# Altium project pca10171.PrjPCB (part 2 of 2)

## Sheet pca10171_memory.SchDoc: =BoardTitle + ' - Memory'
size A3; Organization: Nordic Semiconductor; DocumentNumber: 6; Revision: 1.0.1; SheetNumber: 6; SheetTotal: 10; Author: KOD1; CompanyName: Nordic Semiconductor; DrawnBy: KOD1; DocumentSize: A3

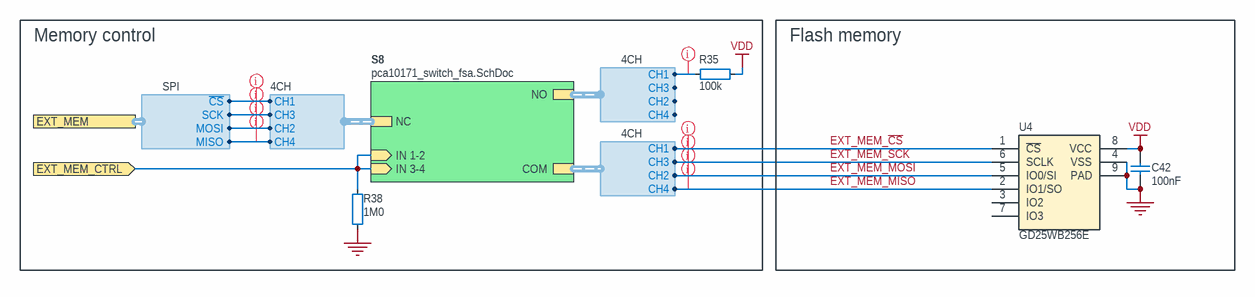
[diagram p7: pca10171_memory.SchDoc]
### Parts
C42  100nF  [CAPC0603X03L_C]
R35  100k  [RESC0603X03L_C]
R38  1M0  [RESC0603X03L_C]
U4  GD25WB256E  [SON127P800X80_HS-9N]

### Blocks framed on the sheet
Memory control: R35 R38
Flash memory: C42 U4

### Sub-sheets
S8 = pca10171_switch_fsa.SchDoc: IN 1-2 (in), COM (harness 4CH), NC (harness 4CH), NO (harness 4CH), IN 3-4 (in)

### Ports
EXT_MEM (harness SPI), EXT_MEM_CTRL (in)

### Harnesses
4CH: CH1, CH2, CH3, CH4
SPI: SCK, ~{CS}, MOSI, MISO

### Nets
GND: C42.1 R38.1 U4.4(VSS) U4.9(PAD)
VDD: C42.2 R35.2 U4.8(VCC)
EXT_MEM_~{CS}: U4.1(~{CS}) ; sheet S8/COM.CH1
EXT_MEM_CTRL: R38.2 ; port EXT_MEM_CTRL, sheet S8/IN 1-2, sheet S8/IN 3-4
EXT_MEM_MISO: U4.2(IO1/SO) ; sheet S8/COM.CH4
EXT_MEM_MOSI: U4.5(IO0/SI) ; sheet S8/COM.CH2
EXT_MEM_SCK: U4.6(SCLK) ; sheet S8/COM.CH3
P0.11: port EXT_MEM.MOSI, sheet S8/NC.CH2
P0.12: port EXT_MEM.MISO, sheet S8/NC.CH4
P0.13/AIN0: port EXT_MEM.SCK, sheet S8/NC.CH3
P0.20/AIN7: port EXT_MEM.~{CS}, sheet S8/NC.CH1
NetR35_1: R35.1 ; sheet S8/NO.CH1

Not connected (* = marked no-connect by the designer): U4 3(IO2) 7(IO3)

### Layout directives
net class GPIO: EXT_MEM_MISO, EXT_MEM_MOSI, EXT_MEM_SCK, EXT_MEM_~{CS}, NetR35_1, P0.11, P0.12, P0.13/AIN0, P0.20/AIN7

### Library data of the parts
C42 = C0201-100n: Capacitor, X5R, ±10%; Manufacturer: N.A.; Part number IPS: 00000001248, 00000002505; Part number Norautron: 262071862; Part number NEMS: 100200078; Note: 16V; Pad Count: 2; Component Status: Active
R35 = R0201-100k: Resistor, ±1%, 0.05W; Manufacturer: N.A.; Part number IPS: 00000001419; Part number Norautron: 26108487; Part number NEMS: 100100080; Pad Count: 2; Note: Chip Res 1%; Component Status: Active
R38 = R0201-1M0: Resistor, ±1%, 0.05W; Manufacturer: N.A.; Part number IPS: 00000001418; Part number Norautron: 26107108; Part number NEMS: 100100093; Note: Chip Res 1%; Pad Count: 2; Component Status: Active
U4 = GD25WB256EYIG: Quad Serial Flash, 256Mbit, 104MHz, 1.65V - 3.6V; Manufacturer: GigaDevice; Part number NEMS: 101900774; Note: N.A.; Pad Count: 8; Component Status: Active

## Sheet pca10171_connectors.SchDoc: =BoardTitle + ' - Connectors'
size A3; Organization: Nordic Semiconductor; DocumentNumber: 7; Revision: 1.0.1; SheetNumber: 7; SheetTotal: 10; Author: KOD1; CompanyName: Nordic Semiconductor; DrawnBy: KOD1; DocumentSize: A3

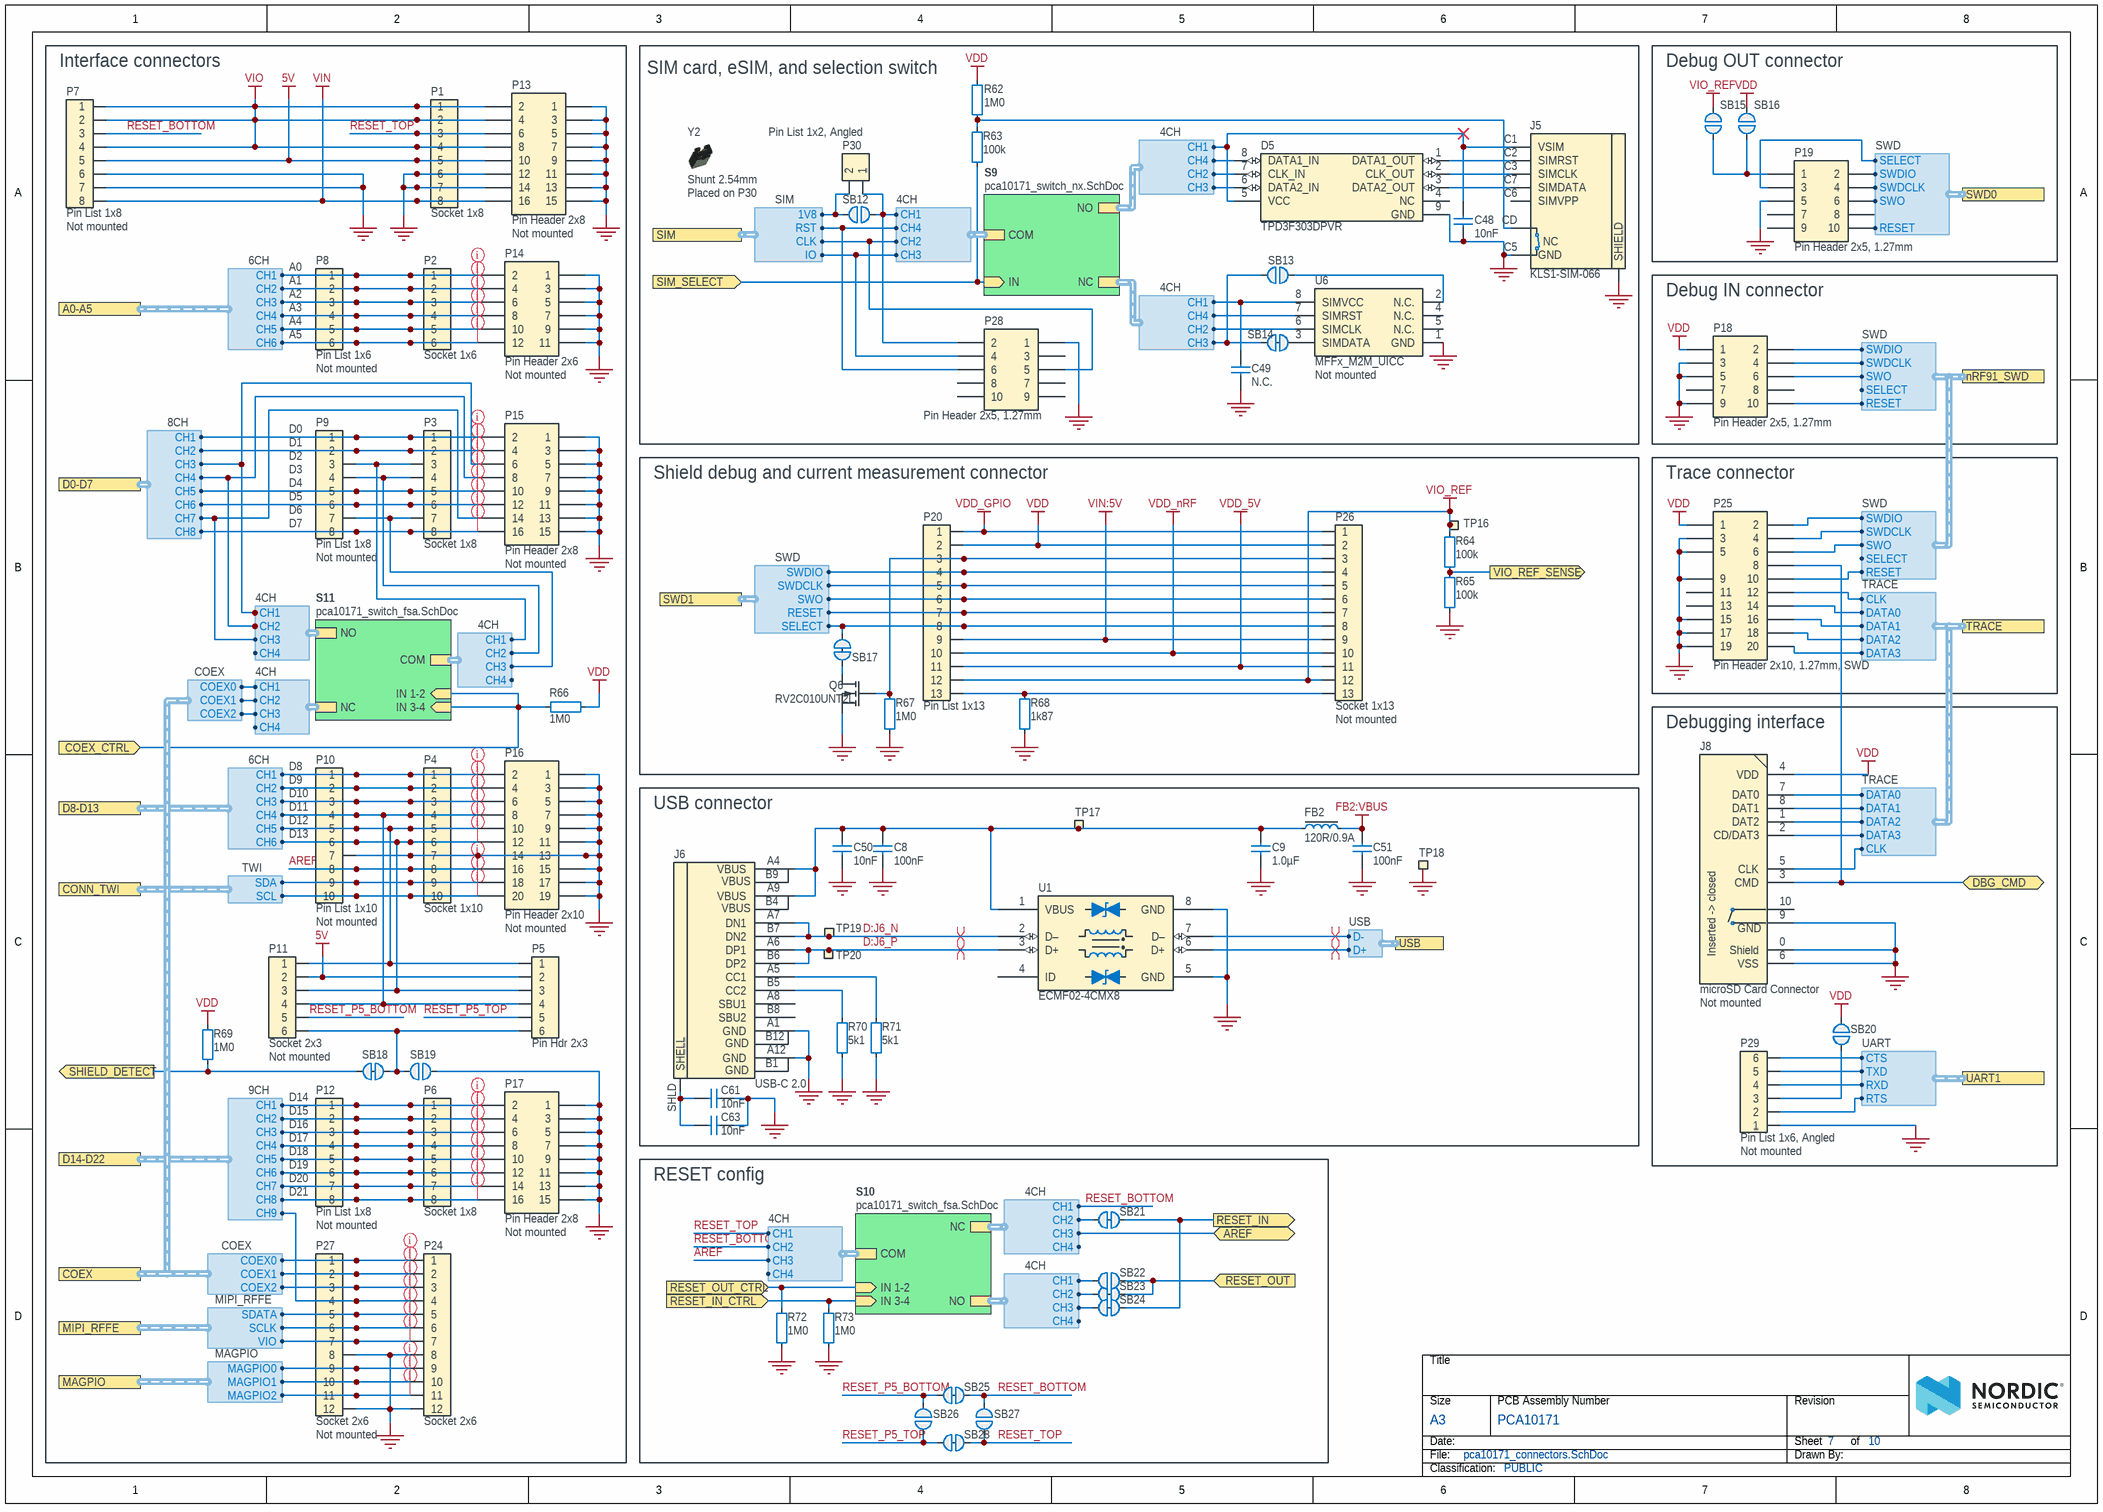
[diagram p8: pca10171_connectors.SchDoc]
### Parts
C8  100nF  [CAPC0603X03L_C]
C9  1.0µF  [CAPC1005X04L]
C48  10nF  [CAPC0603X03L_C]
C49  N.C.  [CAPC0603X03L_C_NC]
C50  10nF  [CAPC0603X03L_C]
C51  100nF  [CAPC0603X03L_C]
C61  10nF  [CAPC1005X04L]
C63  10nF  [CAPC1005X04L]
D5  TPD3F303DPVR  [SON50P210X160X65_HS-9N]
FB2  120R/0.9A  [INDC0603X03L_C]
J5  KLS1-SIM-066  [KLS1-SIM-066]
J6  USB-C 2.0  [SD-80259-001]
J8  microSD Card Connector  Assembly: Not mounted  [Molex_502774-0891]
P1  Socket 1x8  [SOCKET_1x8_SMD]
P2  Socket 1x6  [SOCKET_1x6_SMD]
P3  Socket 1x8  [SOCKET_1x8_SMD]
P4  Socket 1x10  [SOCKET_1x10_SMD]
P5  Pin Hdr 2x3  [HDR_2x3-SMD]
P6  Socket 1x8  [SOCKET_1x8_SMD]
P7  Pin List 1x8  Assembly: Not mounted  [LIST_1x8_SMD-NC]
P8  Pin List 1x6  Assembly: Not mounted  [LIST_1x6_SMD-NC]
P9  Pin List 1x8  Assembly: Not mounted  [LIST_1x8_SMD-NC]
P10  Pin List 1x10  Assembly: Not mounted  [LIST_1x10_SMD-NC]
P11  Socket 2x3  Assembly: Not mounted  [SOCKET_2x3_SMD-2.54mm-bottom-NC]
P12  Pin List 1x8  Assembly: Not mounted  [LIST_1x8_SMD-NC]
P13  Pin Header 2x8  Assembly: Not mounted  [HDR_2x8-NC]
P14  Pin Header 2x6  Assembly: Not mounted  [HDR_2x6-NC]
P15  Pin Header 2x8  Assembly: Not mounted  [HDR_2x8-NC]
P16  Pin Header 2x10  Assembly: Not mounted  [HDR_2x10-NC]
P17  Pin Header 2x8  Assembly: Not mounted  [HDR_2x8-NC]
P18  Pin Header 2x5, 1.27mm  [HDR_2x5-SMD-1.27mm-K]
P19  Pin Header 2x5, 1.27mm  [HDR_2x5-SMD-1.27mm-K]
P20  Pin List 1x13  [LIST_1x13_SMD]
P24  Socket 2x6  [SOCKET_2x6_SMD-2.54mm]
P25  Pin Header 2x10, 1.27mm, SWD  [HDR_2x10-SMD-1.27mm-K-SWD]
P26  Socket 1x13  Assembly: Not mounted  [LIST_1x13_SMD-NC]
P27  Socket 2x6  Assembly: Not mounted  [SOCKET_2x6_SMD-2.54mm]
P28  Pin Header 2x5, 1.27mm  [HDR_2x5-SMD-1.27mm]
P29  Pin List 1x6, Angled  Assembly: Not mounted  [LIST_ANG_1x6-SMD-2.54MM]
P30  Pin List 1x2, Angled  [LIST_ANG_1x2-SMD-2.54MM]
Q6  RV2C010UNT2L  [DFN65P100X40-3L]
R62  1M0  [RESC0603X03L_C]
R63  100k  [RESC0603X03L_C]
R64  100k  [RESC0603X03L_C]
R65  100k  [RESC0603X03L_C]
R66  1M0  [RESC0603X03L_C]
R67  1M0  [RESC0603X03L_C]
R68  1k87  [RESC0603X03L_C]
R69  1M0  [RESC0603X03L_C]
R70  5k1  [RESC0603X03L_C]
R71  5k1  [RESC0603X03L_C]
R72  1M0  [RESC0603X03L_C]
R73  1M0  [RESC0603X03L_C]
SB12  Solderbridge  [Solderbridge]  (value not drawn)  (no BOM)
SB13  Solderbridge  [Solderbridge]  (value not drawn)  (no BOM)
SB14  Solderbridge  [Solderbridge_Shorted]  (value not drawn)  (net tie, no BOM)
SB15  Solderbridge  [Solderbridge]  (value not drawn)  (no BOM)
SB16  Solderbridge  [Solderbridge]  (value not drawn)  (no BOM)
SB17  Solderbridge  [Solderbridge_Shorted]  (value not drawn)  (net tie, no BOM)
SB18  Solderbridge  [Solderbridge_Shorted]  (value not drawn)  (net tie, no BOM)
SB19  Solderbridge  [Solderbridge]  (value not drawn)  (no BOM)
SB20  Solderbridge  [Solderbridge]  (value not drawn)  (no BOM)
SB21  Solderbridge  [Solderbridge_Shorted]  (value not drawn)  (net tie, no BOM)
SB22  Solderbridge  [Solderbridge]  (value not drawn)  (no BOM)
SB23  Solderbridge  [Solderbridge_Shorted]  (value not drawn)  (net tie, no BOM)
SB24  Solderbridge  [Solderbridge_Shorted]  (value not drawn)  (net tie, no BOM)
SB25  Solderbridge  [Solderbridge_Shorted]  (value not drawn)  (net tie, no BOM)
SB26  Solderbridge  [Solderbridge]  (value not drawn)  (no BOM)
SB27  Solderbridge  [Solderbridge]  (value not drawn)  (no BOM)
SB28  Solderbridge  [Solderbridge_Shorted]  (value not drawn)  (net tie, no BOM)
TP16  Ø1.5mm,SMD  [TP_SMD_D1.5mm]  (value not drawn)  (no BOM)
TP17  Ø1.5mm,SMD  [TP_SMD_D1.5mm]  (value not drawn)  (no BOM)
TP18  Ø1.5mm,SMD  [TP_SMD_D1.5mm]  (value not drawn)  (no BOM)
TP19  Ø1.5mm,SMD  [TP_SMD_D1.5mm]  (value not drawn)  (no BOM)
TP20  Ø1.5mm,SMD  [TP_SMD_D1.5mm]  (value not drawn)  (no BOM)
U1  ECMF02-4CMX8  [UFDFN50P120X250X55-8N]
U6  MFFx_M2M_UICC  Assembly: Not mounted  [SON127P600X90_HS-8N]
Y2  Shunt 2.54mm  Assembly: Placed on P30  [Shunt_2.54mm_Horizontal]

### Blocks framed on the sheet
Interface connectors: P1-P17 P24 P27 R66 R69 SB18 SB19
SIM card, eSIM, and selection switch: C48 C49 D5 J5 P28 P30 R62 R63 SB12-SB14 U6 Y2
Debug OUT connector: P19 SB15 SB16
Debug IN connector: P18
Shield debug and current measurement connector: P20 P26 Q6 R64 R65 R67 R68 SB17 TP16
Trace connector: P25
Debugging interface: J8 P29 SB20
USB connector: C8 C9 C50 C51 C61 C63 FB2 J6 R70 R71 TP17-TP20 U1
RESET config: R72 R73 SB21-SB28

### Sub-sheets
S9 = pca10171_switch_nx.SchDoc: IN (in), COM (harness 4CH), NC (harness 4CH), NO (harness 4CH)
S10 = pca10171_switch_fsa.SchDoc: IN 1-2 (in), COM (harness 4CH), NC (harness 4CH), NO (harness 4CH), IN 3-4 (in)
S11 = pca10171_switch_fsa.SchDoc: IN 1-2 (in), COM (harness 4CH), NC (harness 4CH), NO (harness 4CH), IN 3-4 (in)

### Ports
A0-A5 (harness 6CH), AREF (bidir), COEX (harness COEX), COEX_CTRL (in), CONN_TWI (harness TWI), D0-D7 (harness 8CH), D8-D13 (harness 6CH), D14-D22 (harness 9CH), DBG_CMD (bidir), MAGPIO (harness MAGPIO), MIPI_RFFE (harness MIPI_RFFE), nRF91_SWD (harness SWD), RESET_IN (out), RESET_IN_CTRL (in), RESET_OUT (in), RESET_OUT_CTRL (in), SHIELD_DETECT (out), SIM (harness SIM), SIM_SELECT (in), SWD0 (harness SWD), SWD1 (harness SWD), TRACE (harness TRACE), UART1 (harness UART), USB (harness USB), VIO_REF_SENSE (out)

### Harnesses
SWD: SWDIO, SWDCLK, SWO, RESET, SELECT
6CH: CH1, CH2, CH3, CH4, CH5, CH6
8CH: CH1, CH2, CH3, CH4, CH5, CH6, CH7, CH8
COEX: COEX0, COEX2, COEX1
TRACE: CLK, DATA0, DATA1, DATA3, DATA2
USB: D+, D-
UART: RTS, CTS, RXD, TXD
MIPI_RFFE: SDATA, VIO, SCLK
MAGPIO: MAGPIO0, MAGPIO2, MAGPIO1
TWI: SCL, SDA
9CH: CH1, CH2, CH3, CH4, CH5, CH6, CH7, CH8, CH9
4CH: CH1, CH2, CH3, CH4
SIM: CLK, IO, 1V8, RST

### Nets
5V: P1.5 P5.2 P7.5 P11.2 P13.10
FB2:VBUS: C51.2 FB2.2
GND: C8.1 C9.1 C48.2 C49.1 C50.1 C51.1 C61.2 C63.2 D5.9(GND) J5.0(SHIELD) J5.C5(GND) J6.A1(GND) J6.A12(GND) J8.0(Shield) J8.6(VSS) J8.9 P1.6 P1.7 P4.7 P7.6 P7.7 P10.7 P13.1 P13.3 P13.5 P13.7 P13.9 P13.11 P13.12 P13.13 P13.14 P13.15 P14.1 P14.3 P14.5 P14.7 P14.9 P14.11 P15.1 P15.3 P15.5 P15.7 P15.9 P15.11 P15.13 P15.15 P16.1 P16.3 P16.5 P16.7 P16.9 P16.11 P16.13 P16.14 P16.15 P16.17 P16.19 P17.1 P17.3 P17.5 P17.7 P17.9 P17.11 P17.13 P17.15 P18.3 P18.5 P18.9 P19.5 P24.8 P24.12 P25.3 P25.5 P25.9 P25.15 P25.17 P25.19 P27.8 P27.12 P28.1 P29.1 Q6.2(S) R65.1 R67.2 R68.1 R70.1 R71.1 R72.2 R73.1 SB19.1 TP18.1 U1.5(GND) U1.8(GND) U6.1(GND)
VDD: J8.4(VDD) P18.1 P20.2 P25.1 P26.2 R62.1 R66.1 R69.2 SB16.2 SB20.1
VDD_5V: P20.11 P26.11
VDD_GPIO: P20.1 P26.1
VDD_nRF: P20.10 P26.10
VIN: P1.8 P7.8 P13.16
VIN:5V: P20.9 P26.9
VIO: P1.1 P1.2 P1.4 P7.1 P7.2 P7.4 P13.2 P13.4 P13.8
VIO_REF: P20.12 P26.12 R64.1 SB15.2 TP16.1
AREF: P4.8 P10.8 P16.16 ; sheet S10/COM.CH3
COEX0: P24.1 P27.1 ; port COEX.COEX0, sheet S11/NC.CH1
COEX1: P24.2 P27.2 ; port COEX.COEX1, sheet S11/NC.CH2
COEX2: P24.3 P27.3 ; port COEX.COEX2, sheet S11/NC.CH3
COEX_SELECT: R66.2 ; port COEX_CTRL, sheet S11/IN 1-2, sheet S11/IN 3-4
D:J6_N: J6.A7(DN1) J6.B7(DN2) TP19.1 U1.2(D–)
D:J6_P: J6.A6(DP1) J6.B6(DP2) TP20.1 U1.3(D+)
D_N: U1.7(D–) ; port USB.D-
D_P: U1.6(D+) ; port USB.D+
DBG_CMD: J8.3(CMD) P25.8 ; port DBG_CMD
MAGPIO0: P24.9 P27.9 ; port MAGPIO.MAGPIO0
MAGPIO1: P24.10 P27.10 ; port MAGPIO.MAGPIO1
MAGPIO2: P24.11 P27.11 ; port MAGPIO.MAGPIO2
MIPI_SCLK: P24.6 P27.6 ; port MIPI_RFFE.SCLK
MIPI_SDATA: P24.5 P27.5 ; port MIPI_RFFE.SDATA
MIPI_VIO: P24.7 P27.7 ; port MIPI_RFFE.VIO
P0.00: P3.1 P9.1 P15.2 ; port D0-D7.CH1
P0.01: P3.2 P9.2 P15.4 ; port D0-D7.CH2
P0.02: P15.6 ; port D0-D7.CH3, sheet S11/NO.CH1
P0.03: P15.8 ; port D0-D7.CH4, sheet S11/NO.CH2
P0.04: P3.5 P9.5 P15.10 ; port D0-D7.CH5
P0.05: P3.6 P9.6 P15.12 ; port D0-D7.CH6
P0.06: P15.14 ; port D0-D7.CH7, sheet S11/NO.CH3
P0.07: P3.8 P9.8 P15.16 ; port D0-D7.CH8
P0.08: P4.1 P10.1 P16.2 ; port D8-D13.CH1
P0.09: P4.2 P10.2 P16.4 ; port D8-D13.CH2
P0.10: P4.3 P10.3 P16.6 ; port D8-D13.CH3
P0.11: P4.4 P5.4 P10.4 P11.4 P16.8 ; port D8-D13.CH4
P0.12: P4.5 P5.1 P10.5 P11.1 P16.10 ; port D8-D13.CH5
P0.13/AIN0: P4.6 P5.3 P10.6 P11.3 P16.12 ; port D8-D13.CH6
P0.14/AIN1: P2.1 P8.1 P14.2 ; port A0-A5.CH1
P0.15/AIN2: P2.2 P8.2 P14.4 ; port A0-A5.CH2
P0.16/AIN3: P2.3 P8.3 P14.6 ; port A0-A5.CH3
P0.17/AIN4: P2.4 P8.4 P14.8 ; port A0-A5.CH4
P0.18/AIN5: P2.5 P8.5 P14.10 ; port A0-A5.CH5
P0.19/AIN6: P2.6 P8.6 P14.12 ; port A0-A5.CH6
P0.20/AIN7: port AREF, sheet S10/NC.CH3
P0.21: J8.5(CLK) P6.1 P12.1 P17.2 P25.12 SB22.1 SB23.1 ; port RESET_OUT, port TRACE.CLK, port D14-D22.CH1
P0.22: J8.7(DAT0) P6.2 P12.2 P17.4 P18.6 P25.6 P25.14 ; port nRF91_SWD.SWO, port TRACE.DATA0, port D14-D22.CH2
P0.23: J8.8(DAT1) P6.3 P12.3 P17.6 P25.16 ; port TRACE.DATA1, port D14-D22.CH3
P0.24: J8.1(DAT2) P6.4 P12.4 P17.8 P25.18 ; port TRACE.DATA2, port D14-D22.CH4
P0.25: J8.2(CD/DAT3) P6.5 P12.5 P17.10 P25.20 ; port TRACE.DATA3, port D14-D22.CH5
P0.26: P6.6 P12.6 P17.12 ; port D14-D22.CH6
P0.27: P6.7 P12.7 P17.14 ; port D14-D22.CH7
P0.28: P6.8 P12.8 P17.16 ; port D14-D22.CH8
P0.29: P24.4 P27.4 ; port D14-D22.CH9
P0.30: P4.9 P10.9 P16.18 ; port CONN_TWI.SDA
P0.31: P4.10 P10.10 P16.20 ; port CONN_TWI.SCL
RESET: P18.10 P25.10 ; port nRF91_SWD.RESET
RESET_BOTTOM: P7.3 SB25.1 SB27.1 ; sheet S10/NC.CH1, sheet S10/COM.CH2
RESET_BUTTON: SB21.2 SB24.2 ; port RESET_IN
RESET_IN_CTRL: R73.2 ; port RESET_IN_CTRL, sheet S10/IN 3-4
RESET_OUT_CTRL: R72.1 ; port RESET_OUT_CTRL, sheet S10/IN 1-2
RESET_P5_BOTTOM: P11.5 SB25.2 SB26.2
RESET_P5_TOP: P5.5 SB26.1 SB28.2
RESET_TOP: P1.3 P13.6 SB27.2 SB28.1 ; sheet S10/COM.CH1
SHIELD_DETECT: R69.1 SB18.2 ; port SHIELD_DETECT
SIM_1V8: P30.2 SB12.1 ; port SIM.1V8
SIM_CLK: P28.5 ; sheet S9/COM.CH2, port SIM.CLK
SIM_IO: P28.4 ; sheet S9/COM.CH3, port SIM.IO
SIM_RST: P28.6 ; sheet S9/COM.CH4, port SIM.RST
SIM_SELECT: R63.1 ; port SIM_SELECT, sheet S9/IN
SWD0_SEL: P19.3 ; port SWD0.SELECT
SWD0_SWO: P19.6 ; port SWD0.SWO
SWD1_SEL: P20.8 P26.8 SB17.2 ; port SWD1.SELECT
SWD1_SWO: P20.6 P26.6 ; port SWD1.SWO
SWDCLK: P18.4 P25.4 ; port nRF91_SWD.SWDCLK
SWDIO: P18.2 P25.2 ; port nRF91_SWD.SWDIO
VIO_REF_SENSE: R64.2 R65.2 ; port VIO_REF_SENSE
NetC8_2: C8.2 C9.2 C50.2 FB2.1 J6.A4(VBUS) J6.A9(VBUS) TP17.1 U1.1(VBUS)
NetC48_1: C48.1 D5.5(VCC) J5.C1(VSIM) ; sheet S9/NO.CH1
NetC49_2: C49.2 U6.8(SIMVCC) ; sheet S9/NC.CH1
NetC61_1: C61.1 C63.1 J6.SHLD(SHELL)
NetD5_1: D5.1(DATA1_OUT) J5.C2(SIMRST)
NetD5_2: D5.2(CLK_OUT) J5.C3(SIMCLK)
NetD5_3: D5.3(DATA2_OUT) J5.C7(SIMDATA)
NetD5_6: D5.6(DATA2_IN) ; sheet S9/NO.CH3
NetD5_7: D5.7(CLK_IN) ; sheet S9/NO.CH2
NetD5_8: D5.8(DATA1_IN) ; sheet S9/NO.CH4
NetJ5_CD: J5.CD R62.2 R63.2
NetJ6_A5: J6.A5(CC1) R71.2
NetJ6_B5: J6.B5(CC2) R70.2
NetP3_3: P3.3 P9.3 ; sheet S11/COM.CH1
NetP3_4: P3.4 P9.4 ; sheet S11/COM.CH2
NetP3_7: P3.7 P9.7 ; sheet S11/COM.CH3
NetP5_6: P5.6 P11.6 SB18.1 SB19.2
NetP19_1: P19.1 SB15.1 SB16.1
NetP19_2: P19.2 ; port SWD0.SWDIO
NetP19_4: P19.4 ; port SWD0.SWDCLK
NetP19_10: P19.10 ; port SWD0.RESET
NetP20_3: P20.3 P26.3 Q6.1(G) R67.1
NetP20_4: P20.4 P26.4 ; port SWD1.SWDIO
NetP20_5: P20.5 P26.5 ; port SWD1.SWDCLK
NetP20_7: P20.7 P26.7 ; port SWD1.RESET
NetP20_13: P20.13 P26.13 R68.2
NetP28_2: P28.2 P30.1 SB12.2 ; sheet S9/COM.CH1
NetP29_2: P29.2 ; port UART1.RTS
NetP29_3: P29.3 SB20.2
NetP29_4: P29.4 ; port UART1.RXD
NetP29_5: P29.5 ; port UART1.TXD
NetP29_6: P29.6 ; port UART1.CTS
NetQ6_3: Q6.3(D) SB17.1
NetSB13_1: SB13.1 U6.2(N.C.)
NetSB13_2: SB13.2 SB14.2 ; sheet S9/NC.CH3
NetSB14_1: SB14.1 U6.3(SIMDATA)
NetSB21_1: SB21.1 ; sheet S10/NC.CH2
NetSB22_2: SB22.2 ; sheet S10/NO.CH1
NetSB23_2: SB23.2 ; sheet S10/NO.CH2
NetSB24_1: SB24.1 ; sheet S10/NO.CH3
NetU6_6: U6.6(SIMCLK) ; sheet S9/NC.CH2
NetU6_7: U6.7(SIMRST) ; sheet S9/NC.CH4

Not connected (* = marked no-connect by the designer): D5 4(NC); J5 C6(SIMVPP); J6 A8(SBU1) B8(SBU2); J8 10; P18 7 8; P19 7 8 9; P25 11 13; P28 3 7 8 9 10; U1 4(ID); U6 4(N.C.) 5(N.C.)

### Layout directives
net class GPIO: AREF, COEX0, COEX1, COEX2, MAGPIO0, MAGPIO1, MAGPIO2, MIPI_SCLK, MIPI_SDATA, MIPI_VIO, P0.00, P0.01, P0.02, P0.03, P0.04, P0.05, P0.06, P0.07, P0.08, P0.09, P0.10, P0.11, P0.12, P0.13/AIN0, P0.14/AIN1, P0.15/AIN2, P0.16/AIN3, P0.17/AIN4, P0.18/AIN5, P0.19/AIN6, P0.21, P0.22, P0.23, P0.24, P0.25, P0.26, P0.27, P0.28, P0.29, P0.30, P0.31
differential pair; differential pair class D:J6; net class USB: D:J6_N, D:J6_P
differential pair; differential pair class IMCU; net class USB: D_N, D_P

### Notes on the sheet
- (near P8) A0
- (near P8) A1
- (near P8) A2
- (near P8) A3
- (near P8) A4
- (near P8) A5
- (near P9) D0
- (near P9) D1
- (near P9) D2
- (near P9) D3
- (near P9) D4
- (near P9) D5
- (near P9) D6
- (near P9) D7
- (near P10) D8
- (near P10) D9
- (near P10) D10
- (near P10) D11
- (near P10) D12
- (near P10) D13
- (near P12) D14
- (near P12) D15
- (near P12) D16
- (near P12) D17
- (near P12) D18
- (near P12) D19
- (near P12) D20
- (near P12) D21

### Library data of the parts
C8 C51 = C0201-100n: as C42 on sheet pca10171_memory
C9 = C0402-1µ0-16V-X5R: Capacitor, Ceramic, X5R, ±10%, 16V; Manufacturer: Murata; Manufacturer Part Number: GRT155R61C105KE01D; Part number NEMS: 100200452; Artikkelnr Noca: N.A.; Pad Count: 2; Component Status: Active
C48 C50 = C0201-10n: Capacitor, X7R, ±10%; Manufacturer: N.A.; Part number IPS: 00000003480; Part number Norautron: 26621779; Part number NEMS: 100200067; Note: 10V; Pad Count: 2; Component Status: Active
C49 = C0201-N.C.: Not mounted; Manufacturer: N.A.; Part number NEMS: 100200001; Note: Chip Cap; Assembly: Not mounted; Pad Count: 2; Component Status: Active
C61 C63 = C0402-10n: Capacitor, X7R, ±10%; Manufacturer: N.A.; Part number IPS: 00000007784; Part number NEMS: 100200173; Component Status: Active; Pad Count: 2; Note: 16V; Artikkelnr Noca: 20039166
D5 = TPD3F303DPVR: ESD Protection and EMI Filter for SIM Card Interface; Manufacturer: Texas Instruments; Part number NEMS: 101900729; Note: N.A.; Pad Count: 8; Component Status: Active
FB2 = FB0201-120R@100M-900mA-BLM03PX121SN1D: Ferrite Bead, 120 Ohm @ 100MHz, 900mA, 160 mOhm Max; Manufacturer: Murata; Part number NEMS: 100300405; Component Status: Active; Pad Count: 2; Note: N.A.
J5 = L-KLS1-SIM-066-(6+1)P-H1.37-R: Nano SIM Card Connector, Push-Push, 6-Pin, H1.37mm, with CD Pin; Manufacturer: KLS Electronic; Part number NEMS: 100500776; Note: N.A.; Pad Count: 7; Component Status: Active
J6 = 80259-1021: USB-C Receptacle, 16 Pin, USB 2.0; Manufacturer: Bellweather Electronic Corp.; Part number NEMS: 100500830; Component Status: Active; Pad Count: 16; Note: N.A.; System: Connector
J8 = Molex_502774-0891: 1.10mm Pitch microSD Memory Card Connector, Reverse Mount Surface Mount, Push-Push Type; Manufacturer: Molex; Part number IPS: 00000001284; Part number NEMS: 100500509; Note: N.A.; Pad Count: 14; Component Status: Active
P1 P3 P6 = Socket 1x8 SMD: Socket 1x8, 2.54mm (100mil), SMD; Manufacturer: WCON; Manufacturer Part Number: 2171-108MS0CUNR1; Part number IPS: 00000009963; Part number Norautron: 26032369; Part number NEMS: 100500412; Note: N.A.; Artikkelnr Noca: 55030002; Pad Count: 8; Component Status: Active; System: Connector
P2 = Socket 1x6 SMD: Socket 1x6, 2.54mm (100mil), SMD; Manufacturer: WCON; Manufacturer Part Number: 2171-106MS0CUNR1; Part number IPS: 00000009964; Part number Norautron: 26032370; Part number NEMS: 100500408; Note: N.A.; Artikkelnr Noca: 55030001; Pad Count: 6; Component Status: Active; System: Connector
P4 = Socket 1x10 SMD: Socket 1x10, 2.54mm (100mil), SMD; Manufacturer: WCON; Manufacturer Part Number: 2171-110MS0CUNR1; Part number IPS: 00000009965; Part number Norautron: 26032371; Part number NEMS: 100500416; Note: N.A.; Artikkelnr Noca: 55030004; Pad Count: 10; Component Status: Active; System: Connector
P5 = Pin Header 2x3 SMD: Pin Header 2x3, 2.54mm (100mil) SMD; Manufacturer: WCON; Manufacturer Part Number: 1125-1203S0M116R1; Part number IPS: 00000009966; Part number Norautron: N.A.; Part number NEMS: 100500242; Artikkelnr Noca: 55010007; Pad Count: 6; Component Status: Active; System: Connector
P7 P9 P12 = Pin List 1x8 SMD, N.C.: Pin List 1x8, 2.54mm (100mil), SMD; Manufacturer: WCON; Manufacturer Part Number: 1125-1108S0M116R2; Part number NEMS: 100500330; Note: N.A.; Artikkelnr Noca: 55010006; Pad Count: 8; Component Status: Active; System: Connector
P8 = Pin List 1x6 SMD, N.C.: Pin List 1x6, 2.54mm (100mil), SMD; Manufacturer: WCON; Manufacturer Part Number: 1125-1106S0M116R2; Part number NEMS: 100500321; Note: N.A.; Artikkelnr Noca: 55010026; Pad Count: 6; Component Status: Active; System: Connector
P10 = Pin List 1x10 SMD, N.C.: Pin List 1x10, 2.54mm (100mil), SMD; Manufacturer: WCON; Manufacturer Part Number: 1125-1110S0M116R2; Part number NEMS: 100500338; Note: N.A.; Artikkelnr Noca: 55010028; Pad Count: 10; Component Status: Active; System: Connector
P11 = Socket 2x3 SMD Bottom, N.C.: Socket 2x3, 2.54mm (100mil), SMD; Manufacturer: WCON; Manufacturer Part Number: 2171-203MS0CUNR1; Part number NEMS: 100500434; Note: N.A.; Artikkelnr Noca: 55030010; Pad Count: 6; Component Status: Active; System: Connector
P13 P15 P17 = Pin Header 2x8, N.C.: Pin Header 2x8, 2.54mm (100mil); Manufacturer: N.A.; Part number NEMS: 100500270; Pad Count: 16; Component Status: Active; System: Connector
P14 = Pin Header 2x6, N.C.: Pin Header 2x6, 2.54mm (100mil); Manufacturer: N.A.; Part number NEMS: 100500265; Pad Count: 12; Component Status: Active; System: Connector
P16 = Pin Header 2x10, N.C.: Pin Header 2x10, 2.54mm (100mil); Manufacturer: N.A.; Part number NEMS: 100500274; Pad Count: 20; Component Status: Active; System: Connector
P18 P19 = Pin Header 2x5 SMD, 1.27mm, KS: Pin Header 2x5, 1.27mm (50mil), SMD, Keying Shroud; Manufacturer: WCON; Manufacturer Part Number: 3132-10MS0BK00R1; Part number IPS: 00000009968; Part number NEMS: 100500261; Note: N.A.; Artikkelnr Noca: 55010009; Pad Count: 10; Component Status: Active; System: Connector
P20 = Pin List 1x13 SMD: Pin List 1x13, 2.54mm (100mil), SMD; Manufacturer: N.A.; Part number IPS: 00000002499; Part number NEMS: 100500345; Pad Count: 13; Component Status: Active; System: Connector
P24 P27 = Socket 2x6 SMD: Socket 2x6, 2.54mm (100mil), SMD; Manufacturer: WCON; Manufacturer Part Number: 2171-206MS0CUNR1; Part number NEMS: 100500439; Note: N.A.; Pad Count: 12; Component Status: Active; System: Connector
P25 = Pin Header 2x10 SMD, 1.27mm, KS, SWD (Cabcon): Pin Header 2x10, 1.27mm (50mil), SMD, Keying Shroud, Removed Pin 7; Manufacturer: WCON; Manufacturer Part Number: 3132-20MS0BK00R3; Part number NEMS: 100500841,100500280; Note: N.A.; Pad Count: 19; Component Status: Active; System: Connector
P26 = Socket 1x13 SMD, N.C.: Socket 1x13, 2.54mm (100mil), SMD; Manufacturer: WCON; Manufacturer Part Number: 2171-113MS0CUNR1; Part number NEMS: 100500422; Note: N.A.; Pad Count: 13; Component Status: Active; System: Connector
P28 = Pin Header 2x5 SMD, 1.27mm: Pin Header 2x5, 1.27mm (50mil), SMD; Manufacturer: WCON; Manufacturer Part Number: 1325-1205S0M078R1; Part number IPS: 00000009970; Part number NEMS: 100500259; Note: N.A.; Artikkelnr Noca: 55019196; Pad Count: 10; Component Status: Active; System: Connector
P29 = Pin List Ang 1x6 SMD, 2.54mm: Pin List 1x6, 2.54mm (100mil), Right Angled, SMD; Manufacturer: N.A.; Part number IPS: 00000003922; Part number NEMS: 100500362; Pad Count: 6; Component Status: Active; System: Connector
P30 = Pin List Ang 1x2 SMD, 2.54mm: Pin List 1x2, 2.54mm (100mil), Right Angled, SMD; Manufacturer: WCON; Manufacturer Part Number: 1125B-1102S0Z135R2; Part number IPS: 00000009972; Part number NEMS: 100500354; Note: N.A.; Artikkelnr Noca: 55010023; Pad Count: 2; Component Status: Active; System: Connector
Q6 = RV2C010UNT2L: N-Channel MOSFET, 20V, 1A, 470mOhm, 400mW; Manufacturer: Rohm Semiconductor; Part number IPS: 00000009976; Part number Norautron: 26320026; Part number NEMS: 101300132; Note: N.A.; Artikkelnr Noca: 35010020; Pad Count: 3; Component Status: Active
R62 R66 R67 R69 R72 R73 = R0201-1M0: as R38 on sheet pca10171_memory
R63-R65 = R0201-100k: Resistor, ±1%, 0.05W; Manufacturer: N.A.; Part number IPS: 00000001419; Part number Norautron: 26108487; Part number NEMS: 100100080; Note: Chip Res 1%; Pad Count: 2; Component Status: Active
R68 = R0201-1k87: Resistor, ±1%, 0.05W; Manufacturer: N.A.; Part number NEMS: 100100050; Note: Chip Res 1%; Pad Count: 2; Component Status: Active
R70 R71 = R0201-5k1: Resistor, ±1%, 0.05W; Manufacturer: N.A.; Part number Norautron: 26192285; Part number NEMS: 100100565; Pad Count: 2; Note: Chip Res 1%; Component Status: Active
SB12 SB13 SB15 SB16 SB19 SB20 SB22 SB26 SB27 = Solderbridge: Manufacturer: N.A.; Part number NEMS: 100500458; Pad Count: 2; Component Status: Active; System: Connector
SB14 SB18 SB21 SB23-SB25 SB28 = Solderbridge Shorted: Shorted Solderbridge; Manufacturer: N.A.; Part number NEMS: 100500459; Pad Count: 2; Component Status: Active; System: Connector
SB17 = Solderbridge Shorted: Shorted Solderbridge; Manufacturer: N.A.; Part number NEMS: 100500459; Component Status: Active; Pad Count: 2; System: Connector
TP16-TP20 = TP_SMD_Ø1.5MM: 1.5mm circular SMD testpad; Manufacturer: Nordic Semiconductor; Manufacturer Part Number: N.A.; Part number NEMS: 100500477; Pad Count: 1; Component Status: Active
U1 = ECMF02-4CMX8: 2 Line Common mode filter with ESD protection for USB 2.0 interface; Manufacturer: STMicroelectronics; Part number NEMS: 100800034; Component Status: Active; Pad Count: 8; Note: N.A.
U6 = M2M_UICC: M2M UICC SIM Card; Manufacturer: N.A.; Part number NEMS: 101900595; Pad Count: 8; Component Status: Active
Y2 = SHUNT JUMPER 2.54mm BLACK GOLD Horizontal (obsolete): Shunt Jumper 2.54mm Black; Manufacturer: 3M; Manufacturer Part Number: 969102-0000-DA; Part number IPS: 00000001916; Part number Norautron: N.A.; Part number NEMS: 100500644; Note: SHUNT JUMPER .1" BLACK GOLD, h=6.00mm, w=5.00mm; Artikkelnr Noca: 56099001; Pad Count: 2; System: Connector

## Sheet pca10171_power_supply.SchDoc: =BoardTitle + ' - Power Supply'
size A3; Organization: Nordic Semiconductor; DocumentNumber: 8; Revision: 1.0.1; SheetNumber: 8; SheetTotal: 10; Author: KOD1; CompanyName: Nordic Semiconductor; DrawnBy: KOD1; DocumentSize: A3

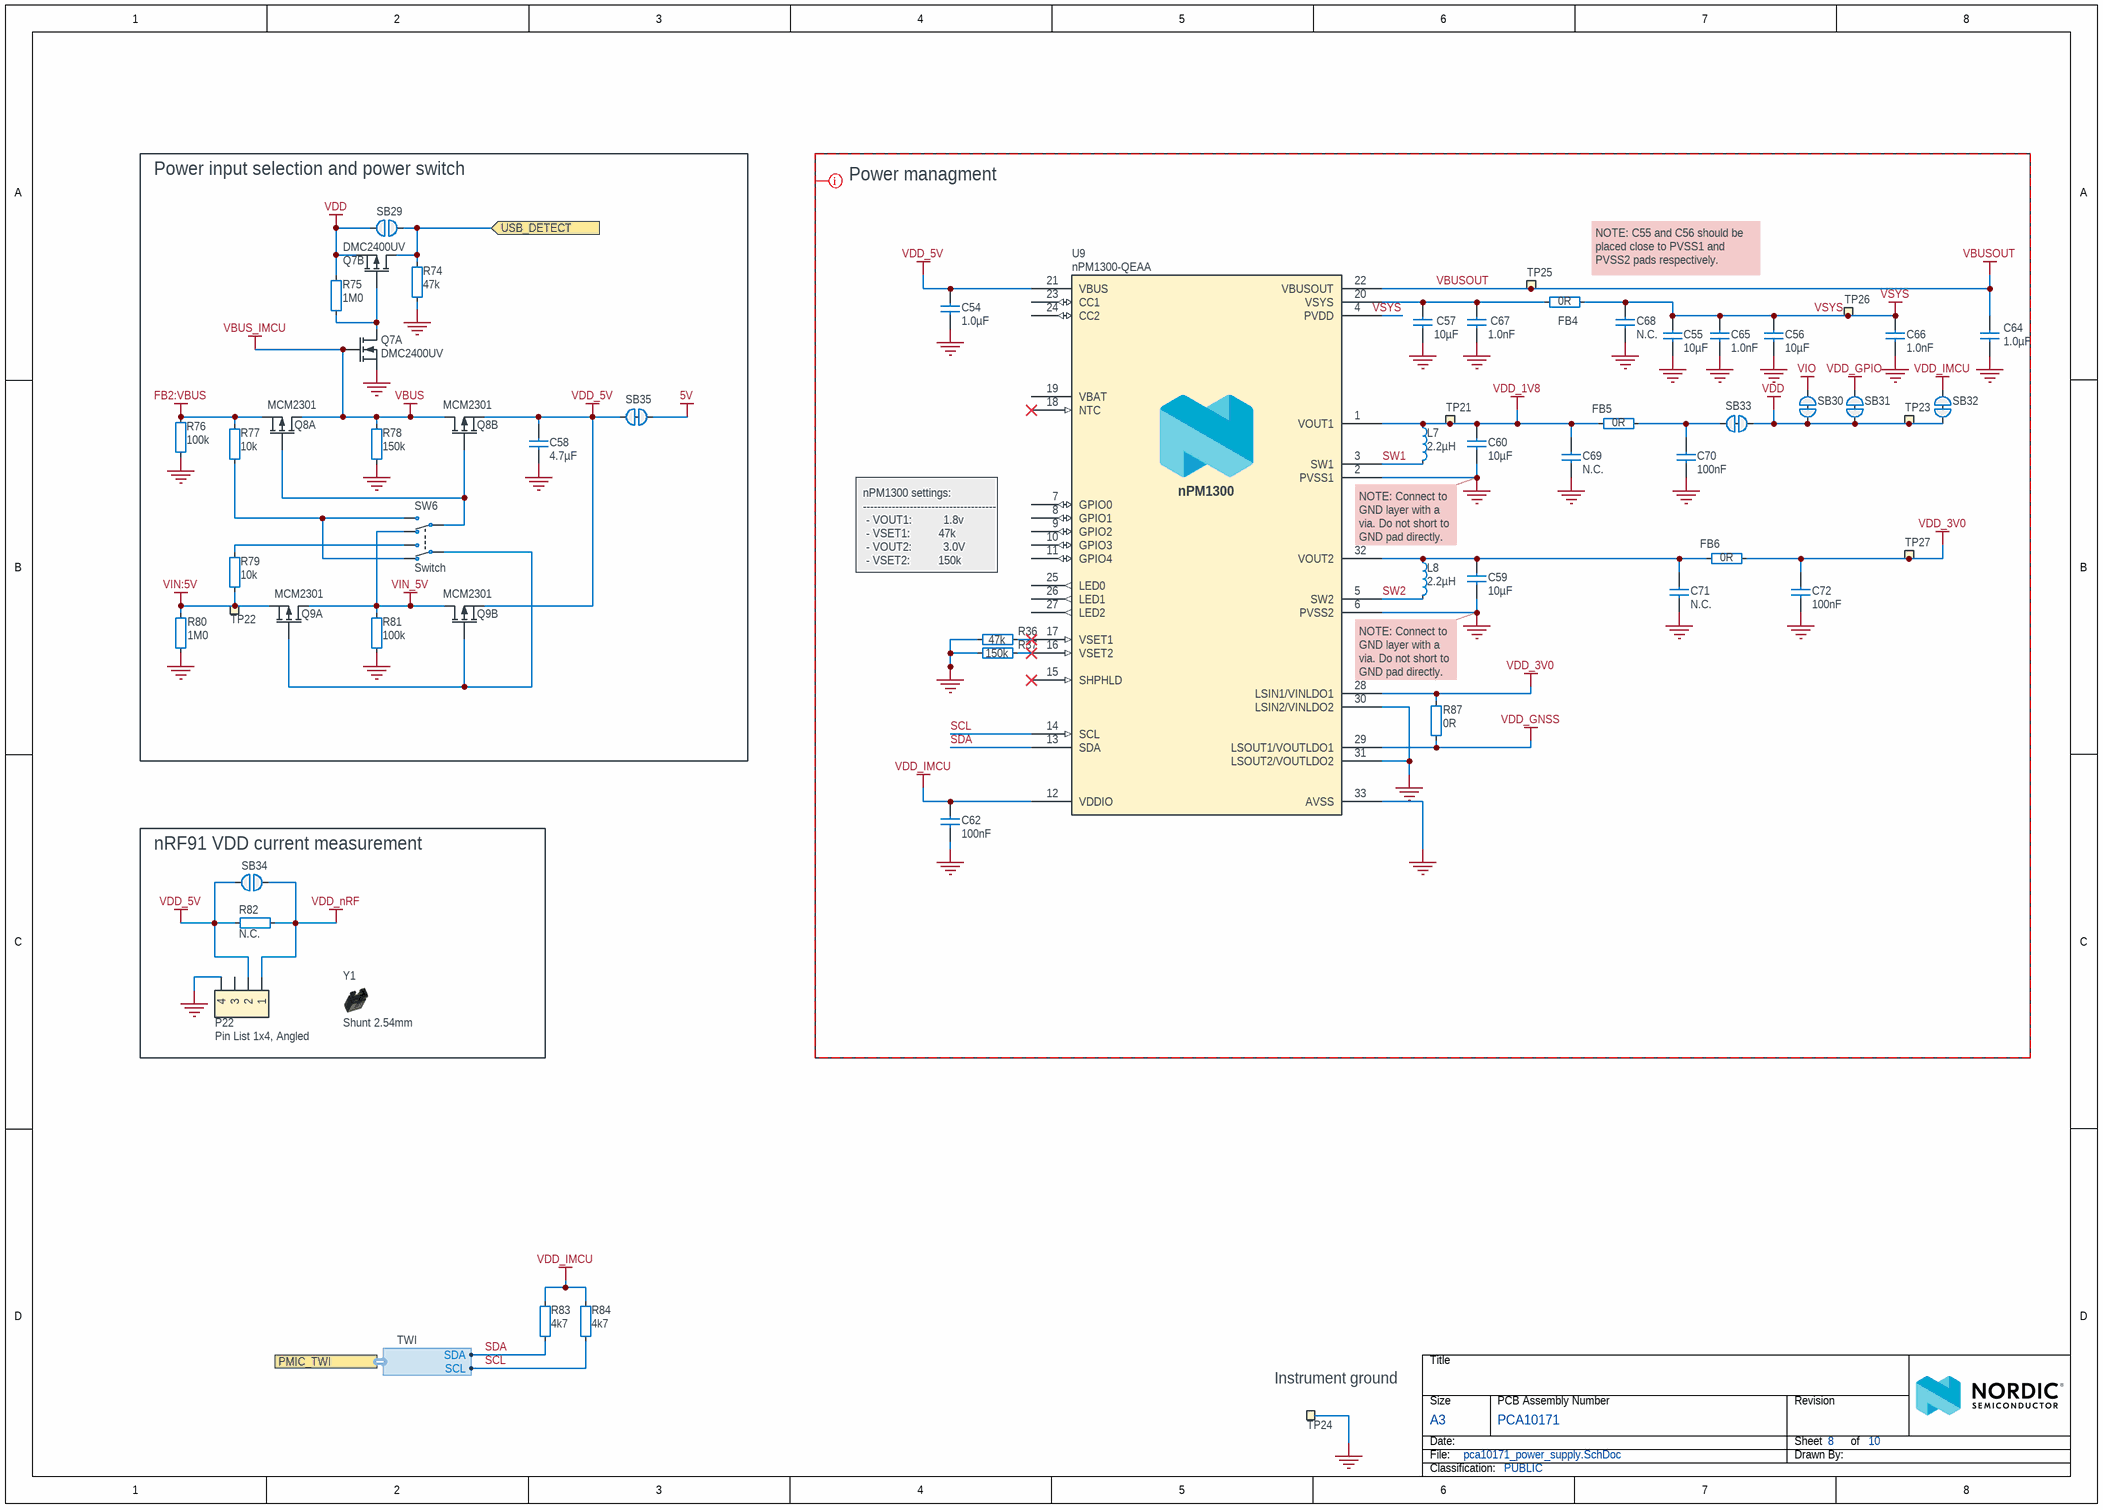
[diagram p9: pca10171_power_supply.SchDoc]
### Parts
C54  1.0µF  [CAPC1608X06L]
C55  10µF  [CAPC1608X06L]
C56  10µF  [CAPC1608X06L]
C57  10µF  [CAPC1608X06L]
C58  4.7µF  [CAPC1608X06L]
C59  10µF  [CAPC1608X06L]
C60  10µF  [CAPC1608X06L]
C62  100nF  [CAPC0603X03L_C]
C64  1.0µF  [CAPC1005X04L]
C65  1.0nF  [CAPC0603X03L_C]
C66  1.0nF  [CAPC0603X03L_C]
C67  1.0nF  [CAPC0603X03L_C]
C68  N.C.  [CAPC1608X06L_NC]
C69  N.C.  [CAPC1608X06L_NC]
C70  100nF  [CAPC1608X06L]
C71  N.C.  [CAPC1608X06L_NC]
C72  100nF  [CAPC1608X06L]
FB4  0R  [RESC2012X11L]
FB5  0R  [RESC2012X11L]
FB6  0R  [RESC2012X11L]
L7  2.2µH  [INDC2016X10N]
L8  2.2µH  [INDC2016X10N]
P22  Pin List 1x4, Angled  [LIST_ANG_1x4-SMD-2.54MM]
Q7  DMC2400UV  [SOTFL50P162X60-6N]  (parts A,B of 2)
Q8  MCM2301  [DFN65P200X200X80_HS-6N]  (parts A,B of 2)
Q9  MCM2301  [DFN65P200X200X80_HS-6N]  (parts A,B of 2)
R36  47k  [RESC0603X03L_C]
R37  150k  [RESC0603X03L_C]
R74  47k  [RESC0603X03L_C]
R75  1M0  [RESC0603X03L_C]
R76  100k  [RESC0603X03L_C]
R77  10k  [RESC0603X03L_C]
R78  150k  [RESC0603X03L_C]
R79  10k  [RESC0603X03L_C]
R80  1M0  [RESC0603X03L_C]
R81  100k  [RESC0603X03L_C]
R82  N.C.  [RESC1005X04L_NC]
R83  4k7  [RESC0603X03L_C]
R84  4k7  [RESC0603X03L_C]
R87  0R  [RESC0603X03L_C]
SB29  Solderbridge  [Solderbridge]  (value not drawn)  (no BOM)
SB30  Solderbridge  [Solderbridge_Shorted_Power]  (value not drawn)  (net tie, no BOM)
SB31  Solderbridge  [Solderbridge_Shorted_Power]  (value not drawn)  (net tie, no BOM)
SB32  Solderbridge  [Solderbridge_Shorted]  (value not drawn)  (net tie, no BOM)
SB33  Solderbridge  [Solderbridge_Shorted_Power]  (value not drawn)  (net tie, no BOM)
SB34  Solderbridge  [Solderbridge]  (value not drawn)  (no BOM)
SB35  Solderbridge  [Solderbridge_Shorted_Power]  (value not drawn)  (net tie, no BOM)
SW6  Switch  [JS102011JAQN]
TP21  Ø1.5mm,SMD  [TP_SMD_D1.5mm]  (value not drawn)  (no BOM)
TP22  Ø1.5mm,SMD  [TP_SMD_D1.5mm]  (value not drawn)  (no BOM)
TP23  Ø1.5mm,SMD  [TP_SMD_D1.5mm]  (value not drawn)  (no BOM)
TP24  TP  [TESTPAD-TH]  (value not drawn)  (no BOM)
TP25  Ø1.5mm,SMD  [TP_SMD_D1.5mm]  (value not drawn)  (no BOM)
TP26  Ø1.5mm,SMD  [TP_SMD_D1.5mm]  (value not drawn)  (no BOM)
TP27  Ø1.5mm,SMD  [TP_SMD_D1.5mm]  (value not drawn)  (no BOM)
U9  nPM1300-QEAA  [Nordic_QFN50P500X500X90-33N]
Y1  Shunt 2.54mm  [Shunt_2.54mm_Horizontal]

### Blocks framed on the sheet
Power input selection and power switch: C58 Q7-Q9 R74-R81 SB29 SB35 SW6 TP22
Power managment: C54-C57 C59 C60 C62 C64-C72 FB4-FB6 L7 L8 R36 R37 R87 SB30-SB33 TP21 TP23 TP25-TP27 U9
nRF91 VDD current measurement: P22 R82 SB34 Y1

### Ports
PMIC_TWI (harness TWI), USB_DETECT (in)

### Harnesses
TWI: SCL, SDA

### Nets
5V: SB35.2
FB2:VBUS: Q8.1(S1) R76.1 R77.1
GND: C54.1 C55.1 C56.1 C57.1 C58.1 C59.1 C60.1 C62.2 C64.1 C65.1 C66.1 C67.1 C68.1 C69.1 C70.1 C71.1 C72.1 P22.4 Q7.1(S1) R36.2 R37.2 R74.1 R76.2 R78.1 R80.2 R81.2 TP24.1 U9.2(PVSS1) U9.6(PVSS2) U9.30(LSIN2/VINLDO2) U9.31(LSOUT2/VOUTLDO2) U9.33(AVSS)
VBUS: Q7.2(G1) Q8.3(D2) Q8.6(D1) R78.2  [also labelled VBUS_IMCU]
VBUSOUT: C64.2 TP25.1 U9.22(VBUSOUT)
VDD: Q7.4(S2) R75.1 SB29.1 SB30.2 SB31.1 SB32.1 SB33.2 TP23.1
VDD_1V8: C60.2 C69.2 FB5.1 L7.1 TP21.1 U9.1(VOUT1)
VDD_3V0: C72.2 FB6.2 R87.1 TP27.1 U9.28(LSIN1/VINLDO1)
VDD_5V: C54.2 C58.2 P22.2 Q8.4(S2) Q9.4(S2) R82.2 SB34.2 SB35.1 U9.21(VBUS)
VDD_GNSS: R87.2 U9.29(LSOUT1/VOUTLDO1)
VDD_GPIO: SB31.2
VDD_IMCU: C62.1 R83.2 R84.2 SB32.2 U9.12(VDDIO)
VDD_nRF: P22.1 R82.1 SB34.1
VIN:5V: Q9.1(S1) R79.2 R80.1 TP22.1
VIN_5V: Q9.3(D2) Q9.6(D1) R81.1 SW6.6(N.C-2)
VIO: SB30.1
VSYS: C55.2 C56.2 C65.2 C66.2 C68.2 FB4.2 TP26.1 U9.4(PVDD)
SCL: R84.1 U9.14(SCL) ; port PMIC_TWI.SCL  [project net IMCU_SCL]
SDA: R83.1 U9.13(SDA) ; port PMIC_TWI.SDA  [project net IMCU_SDA]
SW1: L7.2 U9.3(SW1)
SW2: L8.2 U9.5(SW2)
USB_DETECT: Q7.3(D2) R74.2 SB29.2 ; port USB_DETECT
NetC57_2: C57.2 C67.2 FB4.1 U9.20(VSYS)
NetC59_2: C59.2 C71.2 FB6.1 L8.1 U9.32(VOUT2)
NetC70_2: C70.2 FB5.2 SB33.1
NetQ7_5: Q7.5(G2) Q7.6(D1) R75.2
NetQ8_2: Q8.2(G1) Q8.5(G2) SW6.5(COM-2)
NetQ9_2: Q9.2(G1) Q9.5(G2) SW6.2(COM-1)
NetR36_1: R36.1 U9.17(VSET1)
NetR37_1: R37.1 U9.16(VSET2)
NetR77_2: R77.2 SW6.3(N.C-1) SW6.4(N.O-2)
NetR79_1: R79.1 SW6.1(N.O-1)

Not connected (* = marked no-connect by the designer): P22 3; U9 7(GPIO0) 8(GPIO1) 9(GPIO2) 10(GPIO3) 11(GPIO4) 15(SHPHLD)* 18(NTC)* 19(VBAT) 23(CC1) 24(CC2) 25(LED0) 26(LED1) 27(LED2)

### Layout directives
CompClassName: nPM1300: GND, SCL, SDA, SW1, SW2, VBUSOUT, VDD, VDD_1V8, VDD_3V0, VDD_5V, VDD_GNSS, VDD_GPIO, VDD_IMCU, VIO, VSYS

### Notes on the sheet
- NOTE: C55 and C56 should be placed close to PVSS1 and PVSS2 pads respectively.
- nPM1300 settings:
  -------------------------------------
  - VOUT1:          1.8v
  - VSET1:	        47k
  - VOUT2:          3.0V
  - VSET2:	        150k
- NOTE: Connect to GND layer with a via. Do not short to GND pad directly.
- (near TP24) Instrument ground

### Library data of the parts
C54 = C0603-1µ0-10V-X5R: Capacitor, Ceramic, 1.0µF 10V X5R 0603,±10%; Manufacturer: N.A.; Part number NEMS: 100200528; Component Status: Active; Pad Count: 2
C55-C57 C59 C60 = C0603-10µ-10V-X7T-GRM188D71A106MA73: Capacitor, X7T, ±20%, 10V; Manufacturer: Murata; Part number IPS: 00000004696; Part number NEMS: 100200414; Component Status: Active; Pad Count: 2; Note: 10VDC; Artikkelnr Noca: N.A.
C58 = C0603-4µ7-10V-X5R: Capacitor, Ceramic, X5R, ±10%, 10V; Manufacturer: N.A.; Part number Norautron: 262081761; Part number NEMS: 100200479; Pad Count: 2; Component Status: Active
C62 = C0201-100n: Capacitor, X5R, ±10%; Manufacturer: N.A.; Part number IPS: 00000001248, 00000002505; Part number Norautron: 262071862; Part number NEMS: 100200078; Pad Count: 2; Note: 16V; Component Status: Active
C64 = C0402-1µ0-10V-X5R: Capacitor, Ceramic, X5R, ±10%, 10V; Manufacturer: N.A.; Part number NEMS: 100200482; Pad Count: 2; Component Status: Active
C65-C67 = C0201-1n0: Capacitor, X7R, ±10%, 25V; Manufacturer: N.A.; Part number IPS: 00000003206; Part number NEMS: 100200056; Component Status: Active; Pad Count: 2; Note: 16V
C68 C69 C71 = C0603-N.C.: Not mounted; Manufacturer: N.A.; Part number NEMS: 100200195; Component Status: Active; Pad Count: 2; Note: Chip Cap; Assembly: Not mounted
C70 C72 = C0603-100n: Chip Cap 0603; Manufacturer: N.A.; Part number NEMS: 100200265; Component Status: Active; Pad Count: 2; Note: Chip Cap 1%
FB4-FB6 = R0805-0R: Resistor, ±5%, 0.125W; Manufacturer: N.A.; Part number NEMS: 100100375; Component Status: Active; Pad Count: 2; Note: Chip Res 5%; Artikkelnr Noca: 27089000
L7 L8 = L0806-2µ2-2500mA-73mOhm-CIGT201610EH2R2MNE: Inductor, Irms=2.5A, Isat=2.9A, ±20%, DCR=73mΩ; Manufacturer: Samsung Electro-Mechanics America; Part number Norautron: 26521789; Part number NEMS: 100300400; Component Status: Active; Pad Count: 2; Note: Unshielded Thin Film Inductor; Artikkelnr Noca: N.A.
P22 = Pin List Ang 1x4 SMD, 2.54mm: Pin List 1x4, 2.54mm (100mil), Right Angled, SMD; Manufacturer: WCON; Manufacturer Part Number: 1125B-1104S0Z135CR02; Part number IPS: 00000004780; Part number NEMS: 100500358; Note: N.A.; Pad Count: 4; Component Status: Active; System: Connector
Q7 = DMC2400UV: Dual N & P Ch MOFET, 1.03A/0.7A, 480mOhm, 450mW; Manufacturer: Diodes Incorporated; Part number IPS: 00000007803; Part number NEMS: 101300117; Note: Dual N & P Channel Digital FET; Artikkelnr Noca: N.A.; Pad Count: 6; Component Status: Active
Q8 Q9 = MCM2301: Dual P-Channel MOFET, 3.8A, 90mOhm max, 1.4W; Manufacturer: Micro Commercial Components; Part number NEMS: 101300199; Note: N.A.; Pad Count: 6; Component Status: Active
R36 = R0201-47k: Resistor, ±1%, 0.05W; Manufacturer: N.A.; Part number IPS: 00000001423; Part number NEMS: 100100076; Component Status: Active; Pad Count: 2; Note: Chip Res 1%
R37 = R0201-150k: Resistor, ±1%, 0.05W; Manufacturer: N.A.; Part number IPS: 00000001422; Part number NEMS: 100100082; Component Status: Active; Pad Count: 2; Note: Chip Res 1%
R74 = R0201-47k: Resistor, ±1%, 0.05W; Manufacturer: N.A.; Part number IPS: 00000001423; Part number NEMS: 100100076; Note: Chip Res 1%; Pad Count: 2; Component Status: Active
R75 R80 = R0201-1M0: as R38 on sheet pca10171_memory
R76 R81 = R0201-100k: as R63-R65 on sheet pca10171_connectors
R77 R79 = R0201-10k: Resistor, ±1%, 0.05W; Manufacturer: N.A.; Part number IPS: 00000001255; Part number Norautron: 26107101; Part number NEMS: 100100065; Note: Chip Res 1%; Pad Count: 2; Component Status: Active
R78 = R0201-150k: Resistor, ±1%, 0.05W; Manufacturer: N.A.; Part number IPS: 00000001422; Part number NEMS: 100100082; Note: Chip Res 1%; Pad Count: 2; Component Status: Active
R82 = R0402-N.C.: Not mounted; Manufacturer: N.A.; Part number NEMS: 100100281; Note: Chip Res; Assembly: Not mounted; Pad Count: 2; Component Status: Active
R83 R84 = R0201-4k7: Resistor, ±1%, 0.05W; Manufacturer: N.A.; Part number IPS: 00000001706; Part number NEMS: 100100061; Note: Chip Res 1%; Pad Count: 2; Component Status: Active
R87 = R0201-0R: Resistor, ±5%, 0.05W; Manufacturer: N.A.; Part number IPS: 00000003245; Part number NEMS: 100100001; Component Status: Active; Pad Count: 2; Note: Chip Res 5%
SB29 SB34 = Solderbridge: as SB12 on sheet pca10171_connectors
SB30 SB31 SB33 SB35 = Solderbridge Shorted Power: Shorted Solderbridge Power; Manufacturer: N.A.; Part number NEMS: 100500460; Pad Count: 2; Component Status: Active; System: Connector
SB32 = Solderbridge Shorted: as SB14 on sheet pca10171_connectors
SW6 = Switch-Slide-RA-J-Lead-DPDT-8.5x3.5mm_C&K: SMD slide Switch (ON-ON); Manufacturer: C&K; Manufacturer Part Number: JS202011JAQN; Part number IPS: 00000007811; Part number NEMS: 101500037; Note: N.A.; Pad Count: 6; Component Status: Active
TP21-TP23 TP25-TP27 = TP_SMD_Ø1.5MM: as TP16-TP20 on sheet pca10171_connectors
TP24 = Testpoint TH: Testpoint, through hole; Manufacturer: N.A.; Part number NEMS: 100500464; Pad Count: 1; Component Status: Active
U9 = nPM1300-QEAA: Li-Ion/Li-Polymer USB-C battery charger with high efficiency buck regulators, LDOs or load switches, LED drivers, TWI and VBUSOUT; Manufacturer: Nordic Semiconductor; Part number NEMS: 102000291; Component Status: Active; Pad Count: 33; Note: N.A.
Y1 = SHUNT JUMPER 2.54mm BLACK GOLD Horizontal (obsolete): Shunt Jumper 2.54mm Black; Manufacturer: 3M; Manufacturer Part Number: 969102-0000-DA; Part number IPS: 00000001916; Part number Norautron: N.A.; Part number NEMS: 100500644; Assembly: Placed on "VDD" pins of P22; Note: SHUNT JUMPER .1" BLACK GOLD, h=6.00mm, w=5.00mm; Artikkelnr Noca: 56099001; Pad Count: 2; System: Connector

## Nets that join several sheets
5V: pca10171_connectors (5 pins), pca10171_power_supply (SB35.2)
FB2:VBUS: pca10171_interface_mcu (J4.5), pca10171_connectors (C51.2 FB2.2), pca10171_power_supply (Q8.1 R76.1 R77.1)
GND: pca10171_nrf9151 (63 pins), pca10171_interface_mcu (38 pins), /S1 (C52_S1.2 U7_S1.6), /S2 (C52_S2.2 U7_S2.6 U7_S2.7 U7_S2.15), /S3 (C52_S3.2 U7_S3.6), /S4 (C52_S4.2 U7_S4.6), pca10171_leds_and_buttons (14 pins), /S5 (C52_S5.2 U7_S5.6), /S6 (C52_S6.2 U7_S6.6), /S7 (C53_S7.2 U8_S7.6), pca10171_io_expander (7 pins), pca10171_memory (C42.1 R38.1 U4.4 U4.9), /S8 (C52_S8.2 U7_S8.6), pca10171_connectors (94 pins), /S9 (C53_S9.2 U8_S9.6), /S10 (C52_S10.2 U7_S10.6), /S11 (C52_S11.2 U7_S11.6), pca10171_power_supply (32 pins)
VBUS: pca10171_interface_mcu (R21.1), pca10171_power_supply (Q7.2 Q8.3 Q8.6 R78.2)
VDD: pca10171_nrf9151 (R8.1 SB1.1), pca10171_interface_mcu (R23.2), /S1 (C52_S1.1 U7_S1.14), /S2 (C52_S2.1 U7_S2.14), /S3 (C52_S3.1 U7_S3.14), /S4 (C52_S4.1 U7_S4.14), /S5 (C52_S5.1 U7_S5.14), /S6 (C52_S6.1 U7_S6.14), /S7 (C53_S7.1 U8_S7.14 U8_S7.16), pca10171_memory (C42.2 R35.2 U4.8), /S8 (C52_S8.1 U7_S8.14), pca10171_connectors (10 pins), /S9 (C53_S9.1 U8_S9.14), /S10 (C52_S10.1 U7_S10.14), /S11 (C52_S11.1 U7_S11.14), pca10171_power_supply (8 pins)
VDD_3V0: pca10171_interface_mcu (R33.2), pca10171_leds_and_buttons (R39.2 R40.2 R41.2 R42.2), pca10171_power_supply (5 pins)
VDD_5V: pca10171_connectors (P20.11 P26.11), pca10171_power_supply (9 pins)
VDD_GNSS: pca10171_nrf9151 (C11.2 L3.1), pca10171_power_supply (R87.2 U9.29)
VDD_GPIO: pca10171_nrf9151 (C4.1 C5.1 M1.65 SB2.1), pca10171_connectors (P20.1 P26.1), pca10171_power_supply (SB31.2)
VDD_IMCU: pca10171_interface_mcu (30 pins), pca10171_power_supply (5 pins)
VDD_nRF: pca10171_nrf9151 (C1.1 C2.1 C3.1 FB1.1), pca10171_connectors (P20.10 P26.10), pca10171_power_supply (P22.1 R82.1 SB34.1)
VIN:5V: pca10171_connectors (P20.9 P26.9), pca10171_power_supply (Q9.1 R79.2 R80.1 TP22.1)
VIO: pca10171_connectors (9 pins), pca10171_power_supply (SB30.1)
VIOEXT: /S7 (U8_S7.15), pca10171_io_expander (12 pins)
AREF: pca10171_connectors (P4.8 P10.8 P16.16), /S10 (U7_S10.8)
BTN1_EXT: /S6 (U7_S6.15), pca10171_io_expander (D1.1 R52.1 R53.2)
BTN2_EXT: /S6 (U7_S6.3), pca10171_io_expander (D2.1 R54.1 R55.2)
BTN3_EXT: /S6 (U7_S6.7), pca10171_io_expander (D3.1 R56.1 R57.2)
BTN4_EXT: /S6 (U7_S6.11), pca10171_io_expander (D4.1 R60.1 R61.2)
BUTTON1: pca10171_leds_and_buttons (SW1.2), /S6 (U7_S6.16)
BUTTON2: pca10171_leds_and_buttons (SW2.2), /S6 (U7_S6.4)
BUTTON3: pca10171_leds_and_buttons (SW3.2), /S6 (U7_S6.8)
BUTTON4: pca10171_leds_and_buttons (SW4.2), /S6 (U7_S6.12)
COEX0: pca10171_nrf9151 (M1.52 R6.1 R7.2), pca10171_connectors (P24.1 P27.1), /S11 (U7_S11.1)
COEX1: pca10171_nrf9151 (M1.53), pca10171_connectors (P24.2 P27.2), /S11 (U7_S11.5)
COEX2: pca10171_nrf9151 (M1.54 R3.2), pca10171_connectors (P24.3 P27.3), /S11 (U7_S11.9)
COEX_SELECT: pca10171_interface_mcu (TP11.1 U3.AK14), pca10171_connectors (R66.2), /S11 (U7_S11.2 U7_S11.10)
D_N: pca10171_interface_mcu (U3.B4), pca10171_connectors (U1.7)
D_P: pca10171_interface_mcu (U3.B2), pca10171_connectors (U1.6)
DBG_CMD: pca10171_nrf9151 (SB11.1), pca10171_connectors (J8.3 P25.8)
EXT_MEM_~{CS}: pca10171_memory (U4.1), /S8 (U7_S8.16)
EXT_MEM_CTRL: pca10171_interface_mcu (U3.B14), pca10171_memory (R38.2), /S8 (U7_S8.2 U7_S8.10)
EXT_MEM_MISO: pca10171_memory (U4.2), /S8 (U7_S8.12)
EXT_MEM_MOSI: pca10171_memory (U4.5), /S8 (U7_S8.4)
EXT_MEM_SCK: pca10171_memory (U4.6), /S8 (U7_S8.8)
IMCU_SCL: pca10171_interface_mcu (U3.AF2), pca10171_power_supply (R84.1 U9.14)
IMCU_SDA: pca10171_interface_mcu (U3.AE1), pca10171_power_supply (R83.1 U9.13)
IN 3-4: pca10171_interface_mcu (R32.2), /S4 (U7_S4.10)
INT_EXT: /S7 (U8_S7.11), pca10171_io_expander (R50.1 U5.11)
IOEXP_CTRL: pca10171_interface_mcu (U3.A17), pca10171_leds_and_buttons (R47.2), /S5 (U7_S5.2 U7_S5.10), /S6 (U7_S6.2 U7_S6.10), /S7 (U8_S7.2)
LED1: pca10171_leds_and_buttons (Q4.2 R43.2), /S5 (U7_S5.16)
LED1_EXT: /S5 (U7_S5.15), pca10171_io_expander (U5.7)
LED2: pca10171_leds_and_buttons (Q4.5 R44.2), /S5 (U7_S5.4)
LED2_EXT: /S5 (U7_S5.3), pca10171_io_expander (U5.8)
LED3: pca10171_leds_and_buttons (Q5.2 R45.2), /S5 (U7_S5.8)
LED3_EXT: /S5 (U7_S5.7), pca10171_io_expander (U5.9)
LED4: pca10171_leds_and_buttons (Q5.5 R46.2), /S5 (U7_S5.12)
LED4_EXT: /S5 (U7_S5.11), pca10171_io_expander (U5.10)
MAGPIO0: pca10171_nrf9151 (M1.21), pca10171_connectors (P24.9 P27.9)
MAGPIO1: pca10171_nrf9151 (M1.22), pca10171_connectors (P24.10 P27.10)
MAGPIO2: pca10171_nrf9151 (M1.23), pca10171_connectors (P24.11 P27.11)
MIPI_SCLK: pca10171_nrf9151 (M1.28), pca10171_connectors (P24.6 P27.6)
MIPI_SDATA: pca10171_nrf9151 (M1.27), pca10171_connectors (P24.5 P27.5)
MIPI_VIO: pca10171_nrf9151 (M1.29), pca10171_connectors (P24.7 P27.7)
NetC48_1: pca10171_connectors (C48.1 D5.5 J5.C1), /S9 (U8_S9.15)
NetC49_2: pca10171_connectors (C49.2 U6.8), /S9 (U8_S9.1)
NetD5_6: pca10171_connectors (D5.6), /S9 (U8_S9.7)
NetD5_7: pca10171_connectors (D5.7), /S9 (U8_S9.3)
NetD5_8: pca10171_connectors (D5.8), /S9 (U8_S9.11)
NetP3_3: pca10171_connectors (P3.3 P9.3), /S11 (U7_S11.16)
NetP3_4: pca10171_connectors (P3.4 P9.4), /S11 (U7_S11.4)
NetP3_7: pca10171_connectors (P3.7 P9.7), /S11 (U7_S11.8)
NetP19_2: pca10171_interface_mcu (R28.2), pca10171_connectors (P19.2)
NetP19_4: pca10171_interface_mcu (R29.2), pca10171_connectors (P19.4)
NetP19_10: pca10171_interface_mcu (R30.2), pca10171_connectors (P19.10)
NetP20_4: pca10171_interface_mcu (R25.2), pca10171_connectors (P20.4 P26.4)
NetP20_5: pca10171_interface_mcu (R26.2), pca10171_connectors (P20.5 P26.5)
NetP20_7: pca10171_interface_mcu (R27.2), pca10171_connectors (P20.7 P26.7)
NetP28_2: pca10171_connectors (P28.2 P30.1 SB12.2), /S9 (U8_S9.16)
NetP29_2: pca10171_nrf9151 (SB5.2), /S2 (U7_S2.9), pca10171_connectors (P29.2)
NetP29_4: pca10171_nrf9151 (SB3.2), /S1 (U7_S1.1), pca10171_connectors (P29.4)
NetP29_5: pca10171_nrf9151 (SB4.2), /S1 (U7_S1.5), pca10171_connectors (P29.5)
NetP29_6: pca10171_nrf9151 (SB6.2), /S2 (U7_S2.13), pca10171_connectors (P29.6)
NetR11_2: pca10171_interface_mcu (R11.2 TP3.1), /S1 (U7_S1.16)
NetR12_2: pca10171_interface_mcu (R12.2 TP7.1), /S1 (U7_S1.8)
NetR15_2: pca10171_interface_mcu (R15.2 TP6.1), /S2 (U7_S2.12)
NetR16_2: pca10171_interface_mcu (R16.2 TP10.1), /S2 (U7_S2.4)
NetR19_2: pca10171_interface_mcu (R19.2), /S3 (U7_S3.13)
NetR20_2: pca10171_interface_mcu (R20.2), /S3 (U7_S3.9)
NetR22_2: pca10171_interface_mcu (R22.2), /S3 (U7_S3.1)
NetR35_1: pca10171_memory (R35.1), /S8 (U7_S8.15)
NetSB7_2: pca10171_nrf9151 (SB7.2), /S1 (U7_S1.9)
NetSB8_2: pca10171_nrf9151 (SB8.2), /S1 (U7_S1.13)
NetSB9_2: pca10171_nrf9151 (SB9.2), /S2 (U7_S2.1)
NetSB10_2: pca10171_nrf9151 (SB10.2), /S2 (U7_S2.5)
NetSB13_2: pca10171_connectors (SB13.2 SB14.2), /S9 (U8_S9.9)
NetSB21_1: pca10171_connectors (SB21.1), /S10 (U7_S10.5)
NetSB22_2: pca10171_connectors (SB22.2), /S10 (U7_S10.15)
NetSB23_2: pca10171_connectors (SB23.2), /S10 (U7_S10.3)
NetSB24_1: pca10171_connectors (SB24.1), /S10 (U7_S10.7)
NetU6_6: pca10171_connectors (U6.6), /S9 (U8_S9.5)
NetU6_7: pca10171_connectors (U6.7), /S9 (U8_S9.13)
P0.00: pca10171_nrf9151 (M1.56), /S5 (U7_S5.1), pca10171_connectors (P3.1 P9.1 P15.2)
P0.01: pca10171_nrf9151 (M1.57), /S5 (U7_S5.5), pca10171_connectors (P3.2 P9.2 P15.4)
P0.02: pca10171_nrf9151 (M1.58), pca10171_connectors (P15.6), /S11 (U7_S11.15)
P0.03: pca10171_nrf9151 (M1.59), pca10171_connectors (P15.8), /S11 (U7_S11.3)
P0.04: pca10171_nrf9151 (M1.61), /S5 (U7_S5.9), pca10171_connectors (P3.5 P9.5 P15.10)
P0.05: pca10171_nrf9151 (M1.62), /S5 (U7_S5.13), pca10171_connectors (P3.6 P9.6 P15.12)
P0.06: pca10171_nrf9151 (M1.63), pca10171_connectors (P15.14), /S11 (U7_S11.7)
P0.07: pca10171_nrf9151 (M1.64), pca10171_connectors (P3.8 P9.8 P15.16)
P0.08: pca10171_nrf9151 (M1.67), /S6 (U7_S6.1), pca10171_connectors (P4.1 P10.1 P16.2)
P0.09: pca10171_nrf9151 (M1.68), /S6 (U7_S6.5), pca10171_connectors (P4.2 P10.2 P16.4)
P0.10: pca10171_nrf9151 (M1.69), pca10171_connectors (P4.3 P10.3 P16.6)
P0.11: pca10171_nrf9151 (M1.70), /S8 (U7_S8.5), pca10171_connectors (5 pins)
P0.12: pca10171_nrf9151 (M1.72), /S8 (U7_S8.13), pca10171_connectors (5 pins)
P0.13/AIN0: pca10171_nrf9151 (M1.73), /S8 (U7_S8.9), pca10171_connectors (5 pins)
P0.14/AIN1: pca10171_nrf9151 (M1.74 SB5.1), pca10171_connectors (P2.1 P8.1 P14.2)
P0.15/AIN2: pca10171_nrf9151 (M1.75 SB6.1), pca10171_connectors (P2.2 P8.2 P14.4)
P0.16/AIN3: pca10171_nrf9151 (M1.77 SB9.1), pca10171_connectors (P2.3 P8.3 P14.6)
P0.17/AIN4: pca10171_nrf9151 (M1.78 SB10.1), pca10171_connectors (P2.4 P8.4 P14.8)
P0.18/AIN5: pca10171_nrf9151 (M1.79), /S6 (U7_S6.9), pca10171_connectors (P2.5 P8.5 P14.10)
P0.19/AIN6: pca10171_nrf9151 (M1.80), /S6 (U7_S6.13), /S7 (U8_S7.12), pca10171_connectors (P2.6 P8.6 P14.12)
P0.20/AIN7: pca10171_nrf9151 (M1.2), /S8 (U7_S8.1), /S10 (U7_S10.9)
P0.21: pca10171_nrf9151 (M1.5), pca10171_connectors (7 pins)
P0.22: pca10171_nrf9151 (M1.6), /S3 (U7_S3.4), pca10171_connectors (7 pins)
P0.23: pca10171_nrf9151 (M1.8), pca10171_connectors (5 pins)
P0.24: pca10171_nrf9151 (M1.11), pca10171_connectors (5 pins)
P0.25: pca10171_nrf9151 (M1.12), pca10171_connectors (5 pins)
P0.26: pca10171_nrf9151 (M1.44 SB3.1), pca10171_connectors (P6.6 P12.6 P17.12)
P0.27: pca10171_nrf9151 (M1.45 SB4.1), pca10171_connectors (P6.7 P12.7 P17.14)
P0.28: pca10171_nrf9151 (M1.47 SB7.1), pca10171_connectors (P6.8 P12.8 P17.16)
P0.29: pca10171_nrf9151 (M1.48 SB8.1), pca10171_connectors (P24.4 P27.4)
P0.30: pca10171_nrf9151 (M1.49), /S4 (U7_S4.15), /S7 (U8_S7.4), pca10171_connectors (P4.9 P10.9 P16.18)
P0.31: pca10171_nrf9151 (M1.50), /S4 (U7_S4.3), /S7 (U8_S7.8), pca10171_connectors (P4.10 P10.10 P16.20)
RESET: pca10171_nrf9151 (Q1.2 Q1.5 R9.1 R10.1), /S3 (U7_S3.16), pca10171_connectors (P18.10 P25.10)
RESET_BOTTOM: pca10171_connectors (P7.3 SB25.1 SB27.1), /S10 (U7_S10.1 U7_S10.4)
RESET_BUTTON: pca10171_interface_mcu (R23.1 U3.AL27), /S3 (U7_S3.15), pca10171_leds_and_buttons (SW5.2), pca10171_connectors (SB21.2 SB24.2)
RESET_IN_CTRL: pca10171_interface_mcu (U3.AD2), pca10171_connectors (R73.2), /S10 (U7_S10.10)
RESET_OUT_CTRL: pca10171_interface_mcu (U3.AH2), pca10171_connectors (R72.1), /S10 (U7_S10.2)
RESET_TOP: pca10171_connectors (P1.3 P13.6 SB27.2 SB28.1), /S10 (U7_S10.16)
SCL_EXT: /S7 (U8_S7.7), pca10171_io_expander (R49.1 U5.12)
SDA_EXT: /S7 (U8_S7.3), pca10171_io_expander (R48.1 U5.13)
SHIELD_DETECT: pca10171_interface_mcu (U3.AE31), pca10171_connectors (R69.1 SB18.2)
SIM_1V8: pca10171_nrf9151 (M1.19), pca10171_connectors (P30.2 SB12.1)
SIM_CLK: pca10171_nrf9151 (M1.18), pca10171_connectors (P28.5), /S9 (U8_S9.4)
SIM_IO: pca10171_nrf9151 (M1.17), pca10171_connectors (P28.4), /S9 (U8_S9.8)
SIM_RST: pca10171_nrf9151 (M1.16), pca10171_connectors (P28.6), /S9 (U8_S9.12)
SIM_SELECT: pca10171_interface_mcu (U3.AK8), pca10171_connectors (R63.1), /S9 (U8_S9.2)
SWD0_SEL: pca10171_interface_mcu (U3.B24), pca10171_connectors (P19.3)
SWD0_SWO: pca10171_interface_mcu (U3.B20), pca10171_connectors (P19.6)
SWD1_SEL: pca10171_interface_mcu (U3.AK22), pca10171_connectors (P20.8 P26.8 SB17.2)
SWD1_SWO: pca10171_interface_mcu (U3.AK26), pca10171_connectors (P20.6 P26.6)
SWD3_SWO: pca10171_interface_mcu (U3.W1), /S3 (U7_S3.5)
SWD_CTRL: pca10171_interface_mcu (R24.2 U3.AB2), /S3 (U7_S3.2 U7_S3.10)
SWDCLK: pca10171_nrf9151 (M1.3), /S3 (U7_S3.8), pca10171_connectors (P18.4 P25.4)
SWDIO: pca10171_nrf9151 (M1.4), /S3 (U7_S3.12), pca10171_connectors (P18.2 P25.2)
TGT_SCL: pca10171_interface_mcu (U3.AK12), /S4 (U7_S4.4)
TGT_SDA: pca10171_interface_mcu (U3.AK10), /S4 (U7_S4.16)
TGT_TWI_CTRL: pca10171_interface_mcu (R31.1 U3.AJ1), /S4 (U7_S4.2)
USB_DETECT: pca10171_interface_mcu (U3.Y2), pca10171_power_supply (Q7.3 R74.2 SB29.2)
VCOM0_CTRL: pca10171_interface_mcu (R13.1 U3.R31), /S1 (U7_S1.2)
VCOM0_CTS: pca10171_interface_mcu (R86.1 TP5.1 U3.AL9), /S2 (U7_S2.8)
VCOM0_HWFC: pca10171_interface_mcu (R17.1 U3.AK16), /S2 (U7_S2.2)
VCOM0_RXD: pca10171_interface_mcu (TP4.1 U3.AL19), /S1 (U7_S1.4)
VCOM1_CTRL: pca10171_interface_mcu (R14.2 U3.AK18), /S1 (U7_S1.10)
VCOM1_CTS: pca10171_interface_mcu (R85.1 TP9.1 U3.AL15), /S2 (U7_S2.16)
VCOM1_HWFC: pca10171_interface_mcu (R18.2 U3.AK20), /S2 (U7_S2.10)
VCOM1_RXD: pca10171_interface_mcu (TP8.1 U3.AL21), /S1 (U7_S1.12)
VIO_REF_SENSE: pca10171_interface_mcu (U3.V2), pca10171_connectors (R64.2 R65.2)

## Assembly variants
Full assembly: all parts fitted
Release: not fitted C16 C18 C19 C21 C22 C23 C49 C68 C69 C71 J8 L4 L5 P7 P8 P9 P10 P11 P12 P13 P14 P15 P16 P17 P26 P27 P29 R9 R23 R59 R82 U6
